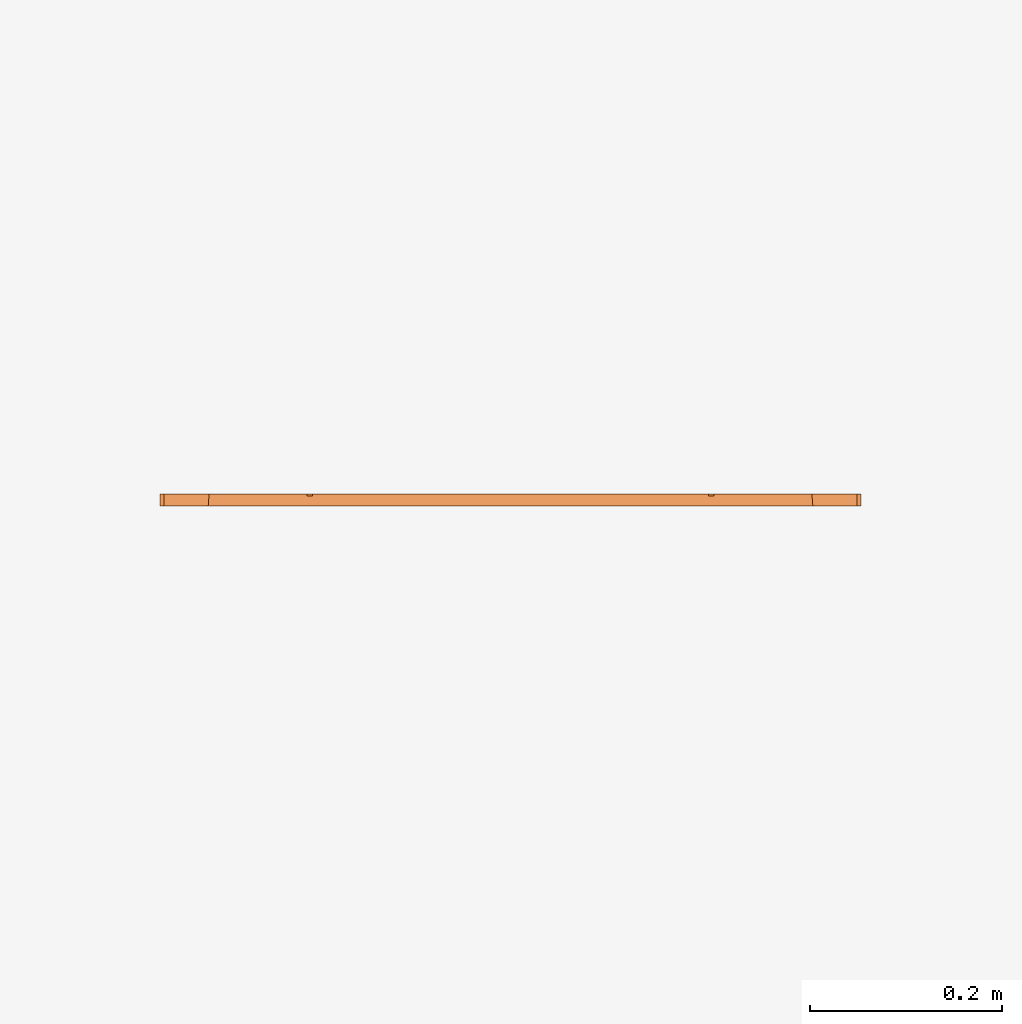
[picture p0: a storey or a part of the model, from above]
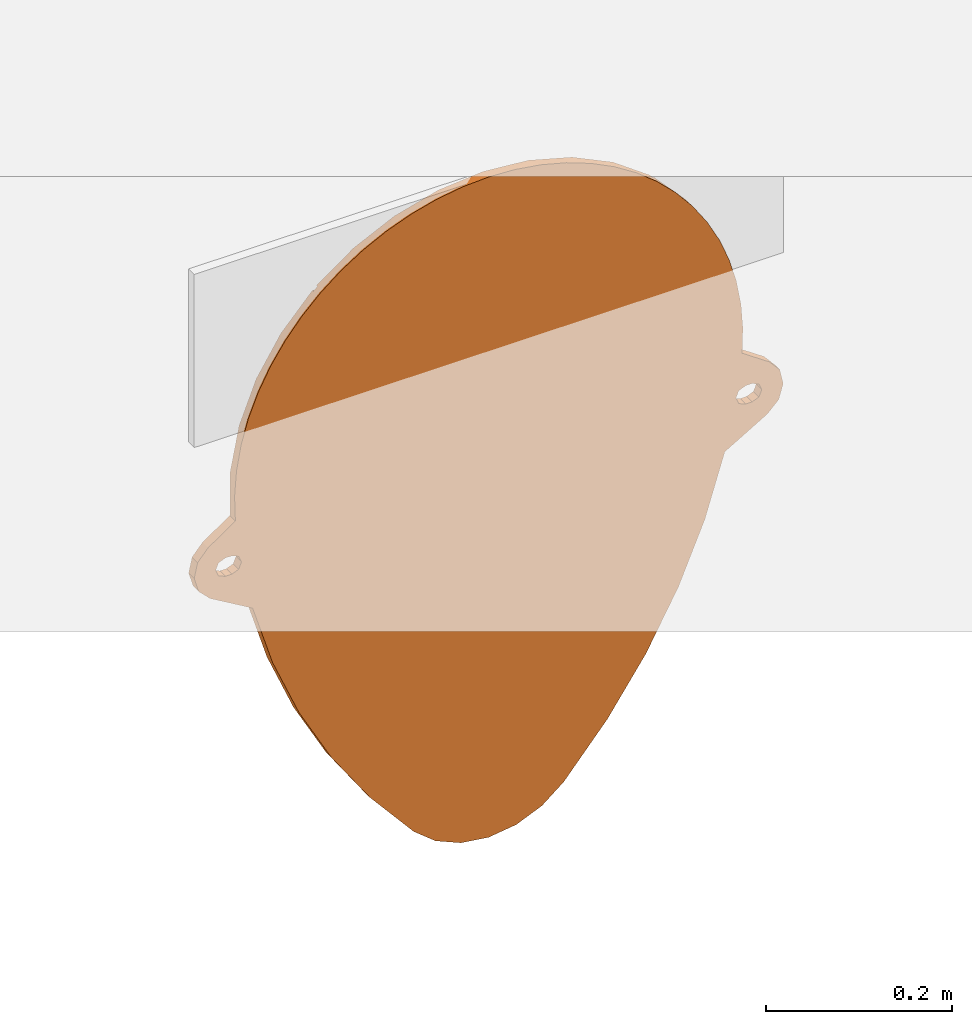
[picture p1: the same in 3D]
Properties of the parts of a building model (IFC2X3)

# File
Description: ViewDefinition [CoordinationView]
File name: 32835 - Closing End Cap (at Female end).ifc
Time: 2013-07-11T17:10:50
Written by: Autodesk Revit 2013
Made in: 20120221_2030(x64)

# IfcProject, Project Number
LongName: Project Name; Phase: Project Status

# IfcSite, Default
RefLatitude: 42, 21, 30, 344238; RefLongitude: -71, -3, -35, -194702; RefElevation: 0 mm

# IfcBuilding
Pset_BuildingCommon - NumberOfStoreys: 1
Other - Project Status: Project Status; Project Issue Date: Issue Date; Project Number: Project Number; Client Name: Owner; Project Name: Project Name; Project Address: ## Street City, State Zip

# IfcBuildingStorey, Level 1
LongName: Level 1; Elevation: 0 mm
Constraints - Elevation Base: 0; Elevation: 0 mm
Graphics - Symbol: M_Level Head - Circle: M_Level Head - Circle; Color: 0; Symbol at End 2 Default: yes; Symbol at End 1 Default: no; Line Pattern: Center; Line Weight: 1
Dimensions - Computation Height: 0 mm
Identity Data - Structural: no; Building Story: yes; Name: Level 1

# IfcBuildingElementProxy: Closing End Cap (at Female end), Closing End Cap (at Female end):Closing End Cap (at Female end):Closing End Cap (at Female end):506148
In: Level 1
Phasing - Phase Created: New Construction
Constraints - Moves With Nearby Elements: no; Level: Level: Level 1
Dimensions - Volume: 4962663 mm3; End Cap_Depth: 570.2 mm
Pset_BuildingElementProxyCommon - Reference: Closing End Cap (at Female end)

# IfcOpeningElement: Recess
In: Level 1
Phasing - Phase Created: New Construction
Constraints - Room Bounding: yes; Level: Level: Level 1; Height Offset From Level: 0 mm; Related to Mass: no
Dimensions - Perimeter: 50000 mm; Volume: 54034013373 mm3; Area: 135090000 mm2; Thickness: 400 mm
Structural - Structural: no; Enable Analytical Model: no
Analytical Properties - Roughness: 1; Absorptance: 0.1
Construction - Function: 0; Default Thickness: 400 mm
Materials and Finishes - Structural Material: Plant
Graphics - Coarse Scale Fill Color: 0

# IfcSlab: Floor:Generic Floor - 400mm, Floor:Generic Floor - 400mm:193825
In: Level 1
PredefinedType: FLOOR; Material: Plant 400 mm
Phasing - Phase Created: New Construction
Constraints - Room Bounding: yes; Level: Level: Level 1; Height Offset From Level: 0 mm; Related to Mass: no
Dimensions - Perimeter: 50000 mm; Volume: 54034013373 mm3; Area: 135090000 mm2; Thickness: 400 mm
Structural - Structural: no; Enable Analytical Model: no
Pset_SlabCommon - Reference: Generic Floor - 400mm; IsExternal: no; LoadBearing: yes
Analytical Properties - Roughness: 1; Absorptance: 0.1
Construction - Function: 0; Default Thickness: 400 mm
Materials and Finishes - Structural Material: Plant
Graphics - Coarse Scale Fill Color: 0
